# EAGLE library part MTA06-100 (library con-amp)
AMP connector

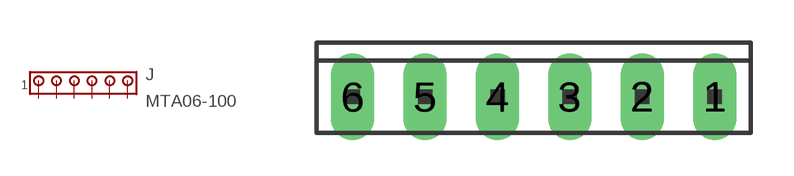
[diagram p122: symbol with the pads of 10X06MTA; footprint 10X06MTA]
Designator prefix J

## MTA06-100  [10X06MTA]
1  1  pas
2  2  pas
3  3  pas
4  4  pas
5  5  pas
6  6  pas

## Footprint 10X06MTA (pad centres in mm)
AMP MTA connector Source: http://ecommas.tycoelectronics.com .. ENG_CD_640456_W.pdf
drill 1.016 long: 1 6.35,0; 2 3.81,0; 3 1.27,0; 4 -1.27,0; 5 -3.81,0; 6 -6.35,0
